VERSION 5.7 ;
  NOWIREEXTENSIONATPIN ON ;
  DIVIDERCHAR "/" ;
  BUSBITCHARS "[]" ;
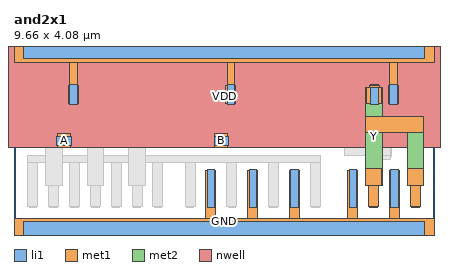
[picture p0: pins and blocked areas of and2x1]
MACRO and2x1
  CLASS BLOCK ;
  FOREIGN and2x1 ;
  ORIGIN 0.000 0.000 ;
  SIZE 9.660 BY 4.080 ;
  PIN A
    ANTENNAGATEAREA 0.819000 ;
    PORT
      LAYER li1 ;
        RECT 0.985 1.930 1.315 2.120 ;
      LAYER met1 ;
        RECT 1.000 1.870 1.300 2.190 ;
    END
  END A
  PIN B
    ANTENNAGATEAREA 0.819000 ;
    PORT
      LAYER li1 ;
        RECT 4.605 1.930 4.935 2.120 ;
      LAYER met1 ;
        RECT 4.620 1.870 4.920 2.190 ;
    END
  END B
  PIN Y
    ANTENNADIFFAREA 0.659400 ;
    PORT
      LAYER li1 ;
        RECT 8.205 2.870 8.375 3.330 ;
        RECT 8.185 0.490 8.355 1.370 ;
        RECT 9.145 0.490 9.315 1.370 ;
      LAYER met1 ;
        RECT 8.175 3.260 8.405 3.310 ;
        RECT 8.100 2.880 8.460 3.260 ;
        RECT 8.080 2.210 9.420 2.590 ;
        RECT 8.080 1.010 8.460 1.390 ;
        RECT 9.040 1.010 9.420 1.390 ;
        RECT 8.155 0.510 8.385 1.010 ;
        RECT 9.115 0.510 9.345 1.010 ;
      LAYER met2 ;
        RECT 8.080 1.010 8.470 3.260 ;
        RECT 9.040 1.010 9.420 2.590 ;
    END
  END Y
  PIN VDD
    ANTENNADIFFAREA 3.062400 ;
    PORT
      LAYER nwell ;
        RECT -0.230 1.870 9.890 4.410 ;
      LAYER li1 ;
        RECT 0.210 3.915 9.450 4.245 ;
        RECT 1.285 2.870 1.455 3.330 ;
        RECT 4.905 2.870 5.075 3.330 ;
        RECT 8.645 2.870 8.815 3.330 ;
      LAYER met1 ;
        RECT 0.000 3.840 9.660 4.320 ;
        RECT 1.285 3.310 1.455 3.840 ;
        RECT 4.905 3.310 5.075 3.840 ;
        RECT 8.645 3.310 8.815 3.840 ;
        RECT 1.255 2.890 1.485 3.310 ;
        RECT 4.875 2.890 5.105 3.310 ;
        RECT 8.615 2.890 8.845 3.310 ;
    END
  END VDD
  PIN GND
    ANTENNADIFFAREA 4.066200 ;
    PORT
      LAYER li1 ;
        RECT 4.445 0.490 4.615 1.370 ;
        RECT 5.405 0.490 5.575 1.370 ;
        RECT 6.365 0.490 6.535 1.370 ;
        RECT 7.705 0.490 7.875 1.370 ;
        RECT 8.665 0.490 8.835 1.370 ;
        RECT 0.210 -0.165 9.450 0.165 ;
      LAYER met1 ;
        RECT 4.415 0.240 4.645 1.350 ;
        RECT 5.375 0.240 5.605 1.350 ;
        RECT 6.335 0.240 6.565 1.350 ;
        RECT 7.675 0.240 7.905 1.350 ;
        RECT 8.635 0.240 8.865 1.350 ;
        RECT 0.000 -0.240 9.660 0.240 ;
    END
  END GND
  OBS
      LAYER li1 ;
        RECT 0.845 2.870 1.015 3.330 ;
        RECT 4.465 2.870 4.635 3.330 ;
        RECT 8.345 1.660 8.675 1.850 ;
        RECT 0.345 0.490 0.515 1.370 ;
        RECT 0.825 0.490 0.995 1.370 ;
        RECT 1.305 0.490 1.475 1.370 ;
        RECT 1.785 0.490 1.955 1.370 ;
        RECT 2.265 0.490 2.435 1.370 ;
        RECT 2.745 0.490 2.915 1.370 ;
        RECT 3.225 0.490 3.395 1.370 ;
        RECT 3.965 0.490 4.135 1.370 ;
        RECT 4.925 0.490 5.095 1.370 ;
        RECT 5.885 0.490 6.055 1.370 ;
        RECT 6.845 0.490 7.015 1.370 ;
      LAYER met1 ;
        RECT 0.815 3.260 1.045 3.310 ;
        RECT 4.435 3.260 4.665 3.310 ;
        RECT 0.740 2.880 1.100 3.260 ;
        RECT 4.360 2.880 4.720 3.260 ;
        RECT 0.720 2.340 7.900 2.720 ;
        RECT 7.600 1.920 7.900 2.340 ;
        RECT 7.600 1.700 8.660 1.920 ;
        RECT 0.315 1.540 7.045 1.690 ;
        RECT 8.360 1.600 8.660 1.700 ;
        RECT 0.315 0.510 0.545 1.540 ;
        RECT 0.720 1.010 1.100 1.390 ;
        RECT 0.795 0.510 1.025 1.010 ;
        RECT 1.275 0.510 1.505 1.540 ;
        RECT 1.680 1.010 2.060 1.390 ;
        RECT 1.755 0.510 1.985 1.010 ;
        RECT 2.235 0.510 2.465 1.540 ;
        RECT 2.640 1.010 3.020 1.390 ;
        RECT 2.715 0.510 2.945 1.010 ;
        RECT 3.195 0.510 3.425 1.540 ;
        RECT 3.935 0.510 4.165 1.540 ;
        RECT 4.895 0.510 5.125 1.540 ;
        RECT 5.855 0.510 6.085 1.540 ;
        RECT 6.815 0.510 7.045 1.540 ;
      LAYER met2 ;
        RECT 0.720 1.010 1.110 3.260 ;
        RECT 1.680 1.010 2.060 2.740 ;
        RECT 2.640 1.010 3.020 2.740 ;
        RECT 4.340 2.340 4.730 3.260 ;
  END
END and2x1
END LIBRARY

